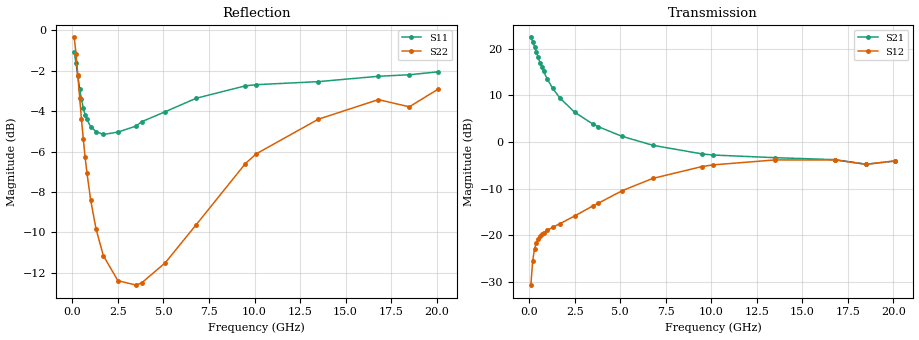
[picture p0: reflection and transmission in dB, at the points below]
!  Infineon Technologies AG
! BFR380L3 , PF131585-7, No.6, Th 09.10.01, soldered on pcb-board, measured with PP GSG850
!  Vce=2.5 V,  Ic=4.0 mA
! Common Emitter S-Parameters:  15. November 2001
#  GHz  S  MA  R  50
! f  S11  S21  S12  S22
! GHz  Mag  Ang  Mag  Ang  Mag  Ang  Mag  Ang
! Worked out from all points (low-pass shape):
!   201 points, 100 MHz to 20.1 GHz, reference 50 ohm
!   highest |S21| = 22.43 dB at 100 MHz (marker M1); lowest = -4.8 dB at 18.5 GHz (marker M2)
!   |S21| within 3 dB of the highest: start of sweep to 387.2 MHz
!   lowest |S11| = -5.2 dB at 1.7 GHz (marker M3), VSWR 3.47, Z = 14.5 - j3.62 ohm
!   |S11| at or under -10 dB: nowhere
!   |S22| runs from -12.7 to -0.3 dB; largest |S21 - S12| = 13
!   S11 on the Smith chart (normalised r, x): 100 MHz: 1.15, -4.06; 400 MHz: 0.35, -1.03; 1 GHz: 0.30, -0.32; 3.8 GHz: 0.28, +0.30; 9.5 GHz: 0.36, +1.10; 20.1 GHz: 0.97, +2.54
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0.1  0.8843 -25.8  13.23 162.9  0.02916 73.6  0.9613 -15.1
0.2  0.8302 -48.5  11.92 148.0  0.05341 65.1  0.8753 -28.1
0.3  0.7717 -68.6  10.53 135.8  0.07108 56.1  0.7743 -38.3
0.4  0.7165 -84.9  9.207 126.0  0.08313 49.8  0.6805 -46.0
0.5  0.6754 -98.7  8.058 118.1  0.09148 45.6  0.6018 -51.9
0.6  0.6416 -110.0  7.112 111.8  0.09789 42.7  0.5376 -56.4
0.7  0.6182 -119.7  6.344 106.4  0.1027 40.6  0.4856 -60.0
0.8  0.6018 -127.9  5.701 101.9  0.1067 39.4  0.4435 -62.9
1  0.5781 -141.1  4.73 94.3  0.1129 38.2  0.3811 -67.4
1.3  0.5617 -156.1  3.755 85.4  0.1215 38.6  0.322 -72.6
1.7  0.5525 -171.0  2.951 75.8  0.1331 40.5  0.2767 -78.6
2.5  0.56 168.3  2.087 60.4  0.1607 44.9  0.2399 -90.9
3.5  0.5796 148.9  1.558 44.7  0.206 48.2  0.2339 -108.4
3.8  0.5941 144.2  1.459 40.9  0.2202 48.4  0.2368 -115.4
5.1  0.6291 125.4  1.151 25.2  0.2994 46.0  0.2657 -140.5
6.8  0.6794 105.0  0.9207 10.2  0.407 37.6  0.3302 -173.6
9.5  0.7291 81.5  0.7443 -4.7  0.545 18.8  0.468 146.3
10.1  0.734 77.2  0.7244 -7.2  0.5677 14.5  0.4948 138.3
13.5  0.7468 59.1  0.6786 -20.3  0.6417 -8.5  0.6026 103.2
16.8  0.77 47.4  0.646 -32.0  0.6408 -25.4  0.674 79.1
18.5  0.7767 45.4  0.5778 -39.7  0.575 -34.0  0.6469 72.9
20.1  0.79 38.5  0.6226 -43.2  0.6285 -39.2  0.7162 61.8
